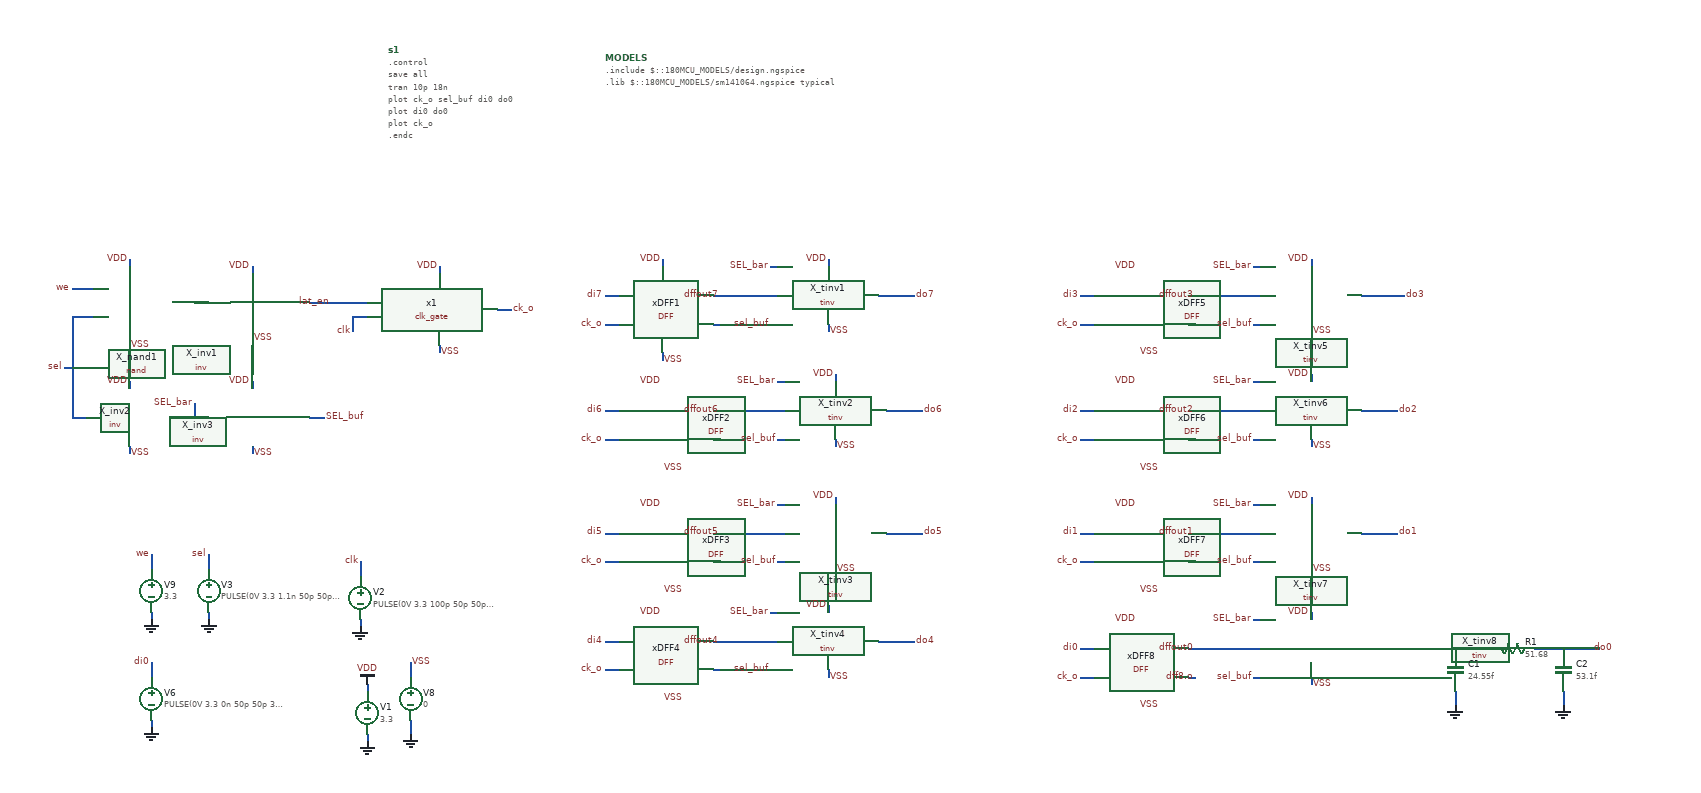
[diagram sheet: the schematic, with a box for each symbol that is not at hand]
v {xschem version=3.0.0 file_version=1.2 }
G {}
K {}
V {}
S {}
E {}
N -320 110 -320 130 {
lab=clk}
N -310 350 -310 360 {
lab=GND}
N -320 190 -320 200 {
lab=GND}
N -310 280 -310 290 {
lab=VDD}
N -530 100 -530 120 {
lab=sel}
N -530 180 -530 190 {
lab=GND}
N -610 250 -610 270 {
lab=di0}
N -610 330 -610 340 {
lab=GND}
N 400 -260 430 -260 {
lab=do7}
N 250 -220 260 -220 {
lab=sel_buf}
N 250 -260 260 -260 {
lab=dffout7}
N 250 -300 260 -300 {
lab=SEL_bar}
N 240 -260 250 -260 {
lab=dffout7}
N 170 -260 190 -260 {
lab=dffout7}
N 330 -310 330 -300 {
lab=VDD}
N 330 -220 330 -210 {
lab=VSS}
N 430 -260 450 -260 {
lab=do7}
N 20 -260 40 -260 {
lab=di7}
N 30 -220 40 -220 {
lab=ck_o}
N 20 -220 30 -220 {
lab=ck_o}
N 170 -100 190 -100 {
lab=dffout6}
N 440 -100 460 -100 {
lab=do6}
N 20 -100 40 -100 {
lab=di6}
N 430 70 440 70 {
lab=do5}
N 170 70 190 70 {
lab=dffout5}
N 440 70 460 70 {
lab=do5}
N 20 70 40 70 {
lab=di5}
N 170 220 190 220 {
lab=dffout4}
N 430 220 450 220 {
lab=do4}
N 20 220 40 220 {
lab=di4}
N 1100 -260 1110 -260 {
lab=do3}
N 1110 -260 1130 -260 {
lab=do3}
N 680 -260 700 -260 {
lab=di3}
N 1090 -100 1100 -100 {
lab=do2}
N 830 -100 850 -100 {
lab=dffout2}
N 1100 -100 1120 -100 {
lab=do2}
N 680 -100 700 -100 {
lab=di2}
N 830 70 850 70 {
lab=dffout1}
N 1100 70 1120 70 {
lab=do1}
N 680 70 700 70 {
lab=di1}
N 1090 230 1100 230 {
lab=#net1}
N 830 230 850 230 {
lab=dffout0}
N 1100 230 1120 230 {
lab=#net1}
N 680 230 700 230 {
lab=di0}
N -720 -90 -700 -90 {
lab=sel}
N -390 -90 -370 -90 {
lab=SEL_buf}
N -640 -140 -640 -130 {
lab=VDD}
N -640 -50 -640 -40 {
lab=VSS}
N -640 -310 -640 -300 {
lab=VDD}
N -640 -200 -640 -190 {
lab=VSS}
N -470 -300 -470 -290 {
lab=VDD}
N -470 -210 -470 -200 {
lab=VSS}
N -550 -250 -530 -250 {
lab=#net2}
N -720 -270 -690 -270 {
lab=we}
N -720 -230 -690 -230 {
lab=sel}
N -720 -230 -720 -90 {
lab=sel}
N -730 -160 -720 -160 {
lab=sel}
N -390 -250 -310 -250 {
lab=lat_en}
N -330 -230 -310 -230 {
lab=clk}
N -330 -230 -330 -210 {
lab=clk}
N -210 -300 -210 -290 {
lab=VDD}
N -210 -190 -210 -180 {
lab=VSS}
N -130 -240 -110 -240 {
lab=ck_o}
N 410 -100 440 -100 {
lab=do6}
N 260 -60 270 -60 {
lab=sel_buf}
N 260 -100 270 -100 {
lab=dffout6}
N 260 -140 270 -140 {
lab=SEL_bar}
N 340 -150 340 -140 {
lab=VDD}
N 340 -60 340 -50 {
lab=VSS}
N 260 110 270 110 {
lab=sel_buf}
N 260 70 270 70 {
lab=dffout5}
N 260 30 270 30 {
lab=SEL_bar}
N 340 20 340 30 {
lab=VDD}
N 340 110 340 120 {
lab=VSS}
N 400 220 430 220 {
lab=do4}
N 250 260 260 260 {
lab=sel_buf}
N 250 220 260 220 {
lab=dffout4}
N 250 180 260 180 {
lab=SEL_bar}
N 330 170 330 180 {
lab=VDD}
N 330 260 330 270 {
lab=VSS}
N 1070 -260 1100 -260 {
lab=do3}
N 920 -220 930 -220 {
lab=sel_buf}
N 920 -260 930 -260 {
lab=dffout3}
N 920 -300 930 -300 {
lab=SEL_bar}
N 910 -260 920 -260 {
lab=dffout3}
N 1000 -310 1000 -300 {
lab=VDD}
N 1000 -220 1000 -210 {
lab=VSS}
N 920 -60 930 -60 {
lab=sel_buf}
N 920 -100 930 -100 {
lab=dffout2}
N 920 -140 930 -140 {
lab=SEL_bar}
N 910 -100 920 -100 {
lab=dffout2}
N 1000 -150 1000 -140 {
lab=VDD}
N 1000 -60 1000 -50 {
lab=VSS}
N 1070 70 1100 70 {
lab=do1}
N 920 110 930 110 {
lab=sel_buf}
N 920 70 930 70 {
lab=dffout1}
N 920 30 930 30 {
lab=SEL_bar}
N 910 70 920 70 {
lab=dffout1}
N 1000 20 1000 30 {
lab=VDD}
N 1000 110 1000 120 {
lab=VSS}
N 920 270 930 270 {
lab=sel_buf}
N 920 230 930 230 {
lab=dffout0}
N 920 190 930 190 {
lab=SEL_bar}
N 910 230 920 230 {
lab=dffout0}
N 1000 180 1000 190 {
lab=VDD}
N 1000 270 1000 280 {
lab=VSS}
N 410 70 430 70 {
lab=do5}
N 1070 230 1090 230 {
lab=#net1}
N 1070 -100 1090 -100 {
lab=do2}
N 830 -260 850 -260 {
lab=dffout3}
N 30 -60 40 -60 {
lab=ck_o}
N 20 -60 30 -60 {
lab=ck_o}
N 30 110 40 110 {
lab=ck_o}
N 20 110 30 110 {
lab=ck_o}
N 30 260 40 260 {
lab=ck_o}
N 20 260 30 260 {
lab=ck_o}
N 190 -260 240 -260 {
lab=dffout7}
N 190 -100 260 -100 {
lab=dffout6}
N 190 70 260 70 {
lab=dffout5}
N 190 220 250 220 {
lab=dffout4}
N 690 -220 700 -220 {
lab=ck_o}
N 680 -220 690 -220 {
lab=ck_o}
N 690 -60 700 -60 {
lab=ck_o}
N 680 -60 690 -60 {
lab=ck_o}
N 690 110 700 110 {
lab=ck_o}
N 680 110 690 110 {
lab=ck_o}
N 690 270 700 270 {
lab=ck_o}
N 680 270 690 270 {
lab=ck_o}
N 850 -260 910 -260 {
lab=dffout3}
N 850 -100 910 -100 {
lab=dffout2}
N 850 70 910 70 {
lab=dffout1}
N 850 230 910 230 {
lab=dffout0}
N -560 -90 -530 -90 {
lab=SEL_bar}
N -550 -110 -550 -90 {
lab=SEL_bar}
N -470 -140 -470 -130 {
lab=VDD}
N -470 -50 -470 -40 {
lab=VSS}
N -250 330 -250 350 {
lab=GND}
N -250 250 -250 270 {
lab=VSS}
N -610 180 -610 190 {
lab=GND}
N -610 110 -610 120 {
lab=we}
N -610 100 -610 110 {
lab=we}
N 170 -220 180 -220 {
lab=#net3}
N 170 -60 180 -60 {
lab=#net4}
N 170 110 180 110 {
lab=#net5}
N 170 260 180 260 {
lab=#net6}
N 830 270 840 270 {
lab=dff8.o}
N 830 110 840 110 {
lab=#net7}
N 830 -60 840 -60 {
lab=#net8}
N 830 -220 840 -220 {
lab=#net9}
N 100 -310 100 -300 {
lab=VDD}
N 100 -180 100 -170 {
lab=VSS}
N 1380 230 1390 230 {
lab=do0}
N 1390 230 1400 230 {
lab=do0}
N 1200 290 1200 300 {
lab=GND}
N 1200 300 1200 310 {
lab=GND}
N 1350 290 1350 310 {
lab=GND}
N 1310 230 1380 230 {
lab=do0}
N 1170 230 1250 230 {
lab=#net1}
N 1120 230 1170 230 {
lab=#net1}
C {lab_pin.sym} -720 -270 0 0 {name=l1 sig_type=std_logic lab=we}
C {lab_pin.sym} -730 -160 0 0 {name=l2 sig_type=std_logic lab=sel}
C {lab_pin.sym} 680 70 0 0 {name=l5 sig_type=std_logic lab=di1}
C {lab_pin.sym} 680 -100 0 0 {name=l6 sig_type=std_logic lab=di2}
C {lab_pin.sym} 680 -260 0 0 {name=l7 sig_type=std_logic lab=di3}
C {lab_pin.sym} 20 220 0 0 {name=l8 sig_type=std_logic lab=di4}
C {lab_pin.sym} 20 70 0 0 {name=l9 sig_type=std_logic lab=di5}
C {lab_pin.sym} 20 -100 0 0 {name=l10 sig_type=std_logic lab=di6}
C {lab_pin.sym} 20 -260 0 0 {name=l11 sig_type=std_logic lab=di7}
C {code_shown.sym} -280 -600 0 0 {name=s1 only_toplevel=false value="
.control
save all
tran 10p 18n
plot ck_o sel_buf di0 do0
plot di0 do0
plot ck_o
.endc
"}
C {devices/code_shown.sym} 20 -590 0 0 {name=MODELS only_toplevel=true
format="tcleval( @value )"
value="
.include $::180MCU_MODELS/design.ngspice
.lib $::180MCU_MODELS/sm141064.ngspice typical
"}
C {vsource.sym} -310 320 0 0 {name=V1 value=3.3}
C {vdd.sym} -310 280 0 0 {name=l22 lab=VDD}
C {gnd.sym} -310 360 0 0 {name=l23 lab=GND}
C {vsource.sym} -320 160 0 0 {name=V2 value="PULSE(0V 3.3 100p 50p 50p 1n 2n)"}
C {gnd.sym} -320 200 0 0 {name=V4 value="PULSE(0V 3.3 100p 50p 50p 1000p 2000p)"}
C {lab_pin.sym} -320 110 0 0 {name=l24 sig_type=std_logic lab=clk}
C {vsource.sym} -530 150 0 0 {name=V3 value="PULSE(0V 3.3 1.1n 50p 50p 2n 4n)"}
C {gnd.sym} -530 190 0 0 {name=V5 value="PULSE(0V 3.3 100p 50p 50p 1000p 2000p)"}
C {lab_pin.sym} -530 100 0 0 {name=l25 sig_type=std_logic lab=sel}
C {vsource.sym} -610 300 0 0 {name=V6 value="PULSE(0V 3.3 0n 50p 50p 3n 6n)"}
C {gnd.sym} -610 340 0 0 {name=V7 value="PULSE(0V 3.3 100p 50p 50p 1000p 2000p)"}
C {lab_pin.sym} -610 250 0 0 {name=l26 sig_type=std_logic lab=di0}
C {xschem_lib/DFFRAM_full_custom/nand.sym} -670 -220 0 0 {name=X_nand1 NF=1}
C {xschem_lib/DFFRAM_full_custom/inv.sym} -530 -210 0 0 {name=X_inv1 NF=2}
C {xschem_lib/DFFRAM_full_custom/inv.sym} -700 -50 0 0 {name=X_inv2 NF=10}
C {xschem_lib/DFFRAM_full_custom/clk_gate.sym} -210 -240 0 0 {name=x1 NF=1}
C {xschem_lib/DFFRAM_full_custom/DFF.sym} 100 -240 0 0 {name=xDFF1 NF=1}
C {xschem_lib/DFFRAM_full_custom/tinv.sym} 260 -220 0 0 {name=X_tinv1 NF=4}
C {lab_wire.sym} 250 -220 0 0 {name=l27 sig_type=std_logic lab=sel_buf}
C {lab_wire.sym} 250 -300 0 0 {name=l28 sig_type=std_logic lab=SEL_bar}
C {lab_wire.sym} 100 -310 0 0 {name=l29 sig_type=std_logic lab=VDD}
C {lab_wire.sym} 100 -170 2 0 {name=l30 sig_type=std_logic lab=VSS}
C {lab_wire.sym} 330 -310 0 0 {name=l31 sig_type=std_logic lab=VDD}
C {lab_wire.sym} 330 -210 2 0 {name=l32 sig_type=std_logic lab=VSS}
C {lab_wire.sym} 20 -220 0 0 {name=l33 sig_type=std_logic lab=ck_o}
C {xschem_lib/DFFRAM_full_custom/DFF.sym} 100 -80 0 0 {name=xDFF2 NF=1}
C {lab_wire.sym} 100 -140 0 0 {name=l34 sig_type=std_logic lab=VDD}
C {lab_wire.sym} 100 -20 2 0 {name=l35 sig_type=std_logic lab=VSS}
C {xschem_lib/DFFRAM_full_custom/DFF.sym} 100 90 0 0 {name=xDFF3 NF=1}
C {lab_wire.sym} 100 30 0 0 {name=l36 sig_type=std_logic lab=VDD}
C {lab_wire.sym} 100 150 2 0 {name=l37 sig_type=std_logic lab=VSS}
C {xschem_lib/DFFRAM_full_custom/DFF.sym} 100 240 0 0 {name=xDFF4 NF=1}
C {lab_wire.sym} 100 180 0 0 {name=l38 sig_type=std_logic lab=VDD}
C {lab_wire.sym} 100 300 2 0 {name=l39 sig_type=std_logic lab=VSS}
C {xschem_lib/DFFRAM_full_custom/DFF.sym} 760 -240 0 0 {name=xDFF5 NF=1}
C {lab_wire.sym} 760 -300 0 0 {name=l40 sig_type=std_logic lab=VDD}
C {lab_wire.sym} 760 -180 2 0 {name=l41 sig_type=std_logic lab=VSS}
C {xschem_lib/DFFRAM_full_custom/DFF.sym} 760 -80 0 0 {name=xDFF6 NF=1}
C {lab_wire.sym} 760 -140 0 0 {name=l48 sig_type=std_logic lab=VDD}
C {lab_wire.sym} 760 -20 2 0 {name=l49 sig_type=std_logic lab=VSS}
C {xschem_lib/DFFRAM_full_custom/DFF.sym} 760 90 0 0 {name=xDFF7 NF=1}
C {lab_wire.sym} 760 30 0 0 {name=l57 sig_type=std_logic lab=VDD}
C {lab_wire.sym} 760 150 2 0 {name=l58 sig_type=std_logic lab=VSS}
C {xschem_lib/DFFRAM_full_custom/DFF.sym} 760 250 0 0 {name=xDFF8 NF=1}
C {lab_wire.sym} 760 190 0 0 {name=l66 sig_type=std_logic lab=VDD}
C {lab_wire.sym} 760 310 2 0 {name=l67 sig_type=std_logic lab=VSS}
C {lab_wire.sym} -370 -90 2 0 {name=l73 sig_type=std_logic lab=SEL_buf}
C {lab_wire.sym} -640 -140 0 0 {name=l74 sig_type=std_logic lab=VDD}
C {lab_wire.sym} -640 -40 2 0 {name=l75 sig_type=std_logic lab=VSS}
C {lab_wire.sym} -640 -310 0 0 {name=l76 sig_type=std_logic lab=VDD}
C {lab_wire.sym} -640 -190 2 0 {name=l77 sig_type=std_logic lab=VSS}
C {lab_wire.sym} -470 -300 0 0 {name=l78 sig_type=std_logic lab=VDD}
C {lab_wire.sym} -470 -200 2 0 {name=l79 sig_type=std_logic lab=VSS}
C {lab_wire.sym} -210 -300 0 0 {name=l80 sig_type=std_logic lab=VDD}
C {lab_wire.sym} -210 -180 2 0 {name=l81 sig_type=std_logic lab=VSS}
C {lab_wire.sym} -110 -240 2 0 {name=l82 sig_type=std_logic lab=ck_o}
C {xschem_lib/DFFRAM_full_custom/tinv.sym} 270 -60 0 0 {name=X_tinv2 NF=4}
C {lab_wire.sym} 260 -60 0 0 {name=l42 sig_type=std_logic lab=sel_buf}
C {lab_wire.sym} 260 -140 0 0 {name=l43 sig_type=std_logic lab=SEL_bar}
C {lab_wire.sym} 340 -150 0 0 {name=l44 sig_type=std_logic lab=VDD}
C {lab_wire.sym} 340 -50 2 0 {name=l45 sig_type=std_logic lab=VSS}
C {xschem_lib/DFFRAM_full_custom/tinv.sym} 270 110 0 0 {name=X_tinv3 NF=4}
C {lab_wire.sym} 260 110 0 0 {name=l46 sig_type=std_logic lab=sel_buf}
C {lab_wire.sym} 260 30 0 0 {name=l47 sig_type=std_logic lab=SEL_bar}
C {lab_wire.sym} 340 20 0 0 {name=l50 sig_type=std_logic lab=VDD}
C {lab_wire.sym} 340 120 2 0 {name=l51 sig_type=std_logic lab=VSS}
C {xschem_lib/DFFRAM_full_custom/tinv.sym} 260 260 0 0 {name=X_tinv4 NF=4}
C {lab_wire.sym} 250 260 0 0 {name=l52 sig_type=std_logic lab=sel_buf}
C {lab_wire.sym} 250 180 0 0 {name=l53 sig_type=std_logic lab=SEL_bar}
C {lab_wire.sym} 330 170 0 0 {name=l54 sig_type=std_logic lab=VDD}
C {lab_wire.sym} 330 270 2 0 {name=l55 sig_type=std_logic lab=VSS}
C {xschem_lib/DFFRAM_full_custom/tinv.sym} 930 -220 0 0 {name=X_tinv5 NF=4}
C {lab_wire.sym} 920 -220 0 0 {name=l56 sig_type=std_logic lab=sel_buf}
C {lab_wire.sym} 920 -300 0 0 {name=l59 sig_type=std_logic lab=SEL_bar}
C {lab_wire.sym} 1000 -310 0 0 {name=l60 sig_type=std_logic lab=VDD}
C {lab_wire.sym} 1000 -210 2 0 {name=l61 sig_type=std_logic lab=VSS}
C {xschem_lib/DFFRAM_full_custom/tinv.sym} 930 -60 0 0 {name=X_tinv6 NF=4}
C {lab_wire.sym} 920 -60 0 0 {name=l62 sig_type=std_logic lab=sel_buf}
C {lab_wire.sym} 920 -140 0 0 {name=l63 sig_type=std_logic lab=SEL_bar}
C {lab_wire.sym} 1000 -150 0 0 {name=l64 sig_type=std_logic lab=VDD}
C {lab_wire.sym} 1000 -50 2 0 {name=l65 sig_type=std_logic lab=VSS}
C {xschem_lib/DFFRAM_full_custom/tinv.sym} 930 110 0 0 {name=X_tinv7 NF=4}
C {lab_wire.sym} 920 110 0 0 {name=l68 sig_type=std_logic lab=sel_buf}
C {lab_wire.sym} 920 30 0 0 {name=l69 sig_type=std_logic lab=SEL_bar}
C {lab_wire.sym} 1000 20 0 0 {name=l70 sig_type=std_logic lab=VDD}
C {lab_wire.sym} 1000 120 2 0 {name=l71 sig_type=std_logic lab=VSS}
C {xschem_lib/DFFRAM_full_custom/tinv.sym} 930 270 0 0 {name=X_tinv8 NF=4}
C {lab_wire.sym} 920 270 0 0 {name=l72 sig_type=std_logic lab=sel_buf}
C {lab_wire.sym} 920 190 0 0 {name=l83 sig_type=std_logic lab=SEL_bar}
C {lab_wire.sym} 1000 180 0 0 {name=l84 sig_type=std_logic lab=VDD}
C {lab_wire.sym} 1000 280 2 0 {name=l85 sig_type=std_logic lab=VSS}
C {lab_pin.sym} 840 230 1 0 {name=l86 sig_type=std_logic lab=dffout0}
C {lab_pin.sym} 840 70 1 0 {name=l87 sig_type=std_logic lab=dffout1}
C {lab_pin.sym} 840 -100 1 0 {name=l88 sig_type=std_logic lab=dffout2}
C {lab_pin.sym} 840 -260 1 0 {name=l89 sig_type=std_logic lab=dffout3}
C {lab_pin.sym} 180 220 1 0 {name=l90 sig_type=std_logic lab=dffout4}
C {lab_pin.sym} 180 70 1 0 {name=l91 sig_type=std_logic lab=dffout5}
C {lab_pin.sym} 180 -100 1 0 {name=l92 sig_type=std_logic lab=dffout6}
C {lab_pin.sym} 180 -260 1 0 {name=l93 sig_type=std_logic lab=dffout7}
C {lab_wire.sym} 20 -60 0 0 {name=l94 sig_type=std_logic lab=ck_o}
C {lab_wire.sym} 20 110 0 0 {name=l95 sig_type=std_logic lab=ck_o}
C {lab_wire.sym} 20 260 0 0 {name=l96 sig_type=std_logic lab=ck_o}
C {lab_wire.sym} 680 -220 0 0 {name=l97 sig_type=std_logic lab=ck_o}
C {lab_wire.sym} 680 -60 0 0 {name=l98 sig_type=std_logic lab=ck_o}
C {lab_wire.sym} 680 110 0 0 {name=l99 sig_type=std_logic lab=ck_o}
C {lab_wire.sym} 680 270 0 0 {name=l100 sig_type=std_logic lab=ck_o}
C {xschem_lib/DFFRAM_full_custom/inv.sym} -530 -50 0 0 {name=X_inv3 NF=8}
C {lab_wire.sym} -550 -110 1 0 {name=l101 sig_type=std_logic lab=SEL_bar}
C {lab_wire.sym} -470 -140 0 0 {name=l102 sig_type=std_logic lab=VDD}
C {lab_wire.sym} -470 -40 2 0 {name=l103 sig_type=std_logic lab=VSS}
C {lab_pin.sym} -330 -210 0 0 {name=l104 sig_type=std_logic lab=clk}
C {lab_pin.sym} 1390 230 2 0 {name=l3 sig_type=std_logic lab=do0}
C {lab_pin.sym} 1120 70 2 0 {name=l105 sig_type=std_logic lab=do1}
C {lab_pin.sym} 1120 -100 2 0 {name=l106 sig_type=std_logic lab=do2}
C {lab_pin.sym} 1130 -260 2 0 {name=l107 sig_type=std_logic lab=do3}
C {lab_pin.sym} 450 220 2 0 {name=l108 sig_type=std_logic lab=do4}
C {lab_pin.sym} 460 70 2 0 {name=l109 sig_type=std_logic lab=do5}
C {lab_pin.sym} 460 -100 2 0 {name=l110 sig_type=std_logic lab=do6}
C {lab_pin.sym} 450 -260 2 0 {name=l111 sig_type=std_logic lab=do7}
C {gnd.sym} -250 350 0 0 {name=l113 lab=GND}
C {lab_wire.sym} -250 250 2 0 {name=l112 sig_type=std_logic lab=VSS}
C {vsource.sym} -250 300 0 0 {name=V8 value=0}
C {vsource.sym} -610 150 0 0 {name=V9 value=3.3}
C {gnd.sym} -610 190 0 0 {name=l13 lab=GND}
C {lab_pin.sym} -610 100 0 0 {name=l12 sig_type=std_logic lab=we}
C {lab_wire.sym} -360 -250 1 0 {name=l14 sig_type=std_logic lab=lat_en}
C {lab_pin.sym} 840 270 3 0 {name=l15 sig_type=std_logic lab=dff8.o}
C {lab_pin.sym} 680 230 0 0 {name=l4 sig_type=std_logic lab=di0}
C {res.sym} 1280 230 1 0 {name=R1
value=51.68
footprint=1206
device=resistor
m=1}
C {capa.sym} 1200 260 0 0 {name=C1
m=1
value=24.55f
footprint=1206
device="ceramic capacitor"}
C {capa.sym} 1350 260 0 0 {name=C2
m=1
value=53.1f
footprint=1206
device="ceramic capacitor"}
C {gnd.sym} 1200 310 0 0 {name=l17 lab=GND}
C {gnd.sym} 1350 310 0 0 {name=l18 lab=GND}
